VERSION 5.8 ;
BUSBITCHARS "[]" ;
DIVIDERCHAR "/" ;
UNITS
    DATABASE MICRONS 1000 ;
END UNITS

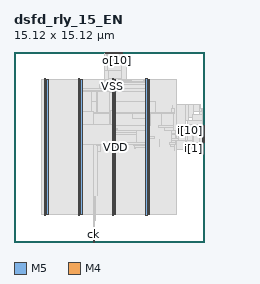
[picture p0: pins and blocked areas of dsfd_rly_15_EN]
MACRO dsfd_rly_15_EN
  FOREIGN dsfd_rly_15_EN 0 0 ;
  CLASS BLOCK ;
  SIZE 15.12 BY 15.12 ;
  PIN ck
    DIRECTION INPUT ;
    USE SIGNAL ;
    PORT
      LAYER M5 ;
        RECT  6.288 0 6.312 0.084 ;
    END
  END ck
  PIN i[0]
    DIRECTION INPUT ;
    USE SIGNAL ;
    PORT
      LAYER M4 ;
        RECT  15.036 7.92 15.12 7.944 ;
    END
  END i[0]
  PIN i[10]
    DIRECTION INPUT ;
    USE SIGNAL ;
    PORT
      LAYER M4 ;
        RECT  15.036 8.88 15.12 8.904 ;
    END
  END i[10]
  PIN i[11]
    DIRECTION INPUT ;
    USE SIGNAL ;
    PORT
      LAYER M4 ;
        RECT  15.036 8.976 15.12 9 ;
    END
  END i[11]
  PIN i[12]
    DIRECTION INPUT ;
    USE SIGNAL ;
    PORT
      LAYER M4 ;
        RECT  15.036 9.072 15.12 9.096 ;
    END
  END i[12]
  PIN i[13]
    DIRECTION INPUT ;
    USE SIGNAL ;
    PORT
      LAYER M4 ;
        RECT  15.036 9.168 15.12 9.192 ;
    END
  END i[13]
  PIN i[14]
    DIRECTION INPUT ;
    USE SIGNAL ;
    PORT
      LAYER M4 ;
        RECT  15.036 9.264 15.12 9.288 ;
    END
  END i[14]
  PIN i[1]
    DIRECTION INPUT ;
    USE SIGNAL ;
    PORT
      LAYER M4 ;
        RECT  15.036 8.016 15.12 8.04 ;
    END
  END i[1]
  PIN i[2]
    DIRECTION INPUT ;
    USE SIGNAL ;
    PORT
      LAYER M4 ;
        RECT  15.036 8.112 15.12 8.136 ;
    END
  END i[2]
  PIN i[3]
    DIRECTION INPUT ;
    USE SIGNAL ;
    PORT
      LAYER M4 ;
        RECT  15.036 8.208 15.12 8.232 ;
    END
  END i[3]
  PIN i[4]
    DIRECTION INPUT ;
    USE SIGNAL ;
    PORT
      LAYER M4 ;
        RECT  15.036 8.304 15.12 8.328 ;
    END
  END i[4]
  PIN i[5]
    DIRECTION INPUT ;
    USE SIGNAL ;
    PORT
      LAYER M4 ;
        RECT  15.036 8.4 15.12 8.424 ;
    END
  END i[5]
  PIN i[6]
    DIRECTION INPUT ;
    USE SIGNAL ;
    PORT
      LAYER M4 ;
        RECT  15.036 8.496 15.12 8.52 ;
    END
  END i[6]
  PIN i[7]
    DIRECTION INPUT ;
    USE SIGNAL ;
    PORT
      LAYER M4 ;
        RECT  15.036 8.592 15.12 8.616 ;
    END
  END i[7]
  PIN i[8]
    DIRECTION INPUT ;
    USE SIGNAL ;
    PORT
      LAYER M4 ;
        RECT  15.036 8.688 15.12 8.712 ;
    END
  END i[8]
  PIN i[9]
    DIRECTION INPUT ;
    USE SIGNAL ;
    PORT
      LAYER M4 ;
        RECT  15.036 8.784 15.12 8.808 ;
    END
  END i[9]
  PIN o[0]
    DIRECTION OUTPUT ;
    USE SIGNAL ;
    PORT
      LAYER M5 ;
        RECT  7.248 15.036 7.272 15.12 ;
    END
  END o[0]
  PIN o[10]
    DIRECTION OUTPUT ;
    USE SIGNAL ;
    PORT
      LAYER M5 ;
        RECT  8.208 15.036 8.232 15.12 ;
    END
  END o[10]
  PIN o[11]
    DIRECTION OUTPUT ;
    USE SIGNAL ;
    PORT
      LAYER M5 ;
        RECT  8.304 15.036 8.328 15.12 ;
    END
  END o[11]
  PIN o[12]
    DIRECTION OUTPUT ;
    USE SIGNAL ;
    PORT
      LAYER M5 ;
        RECT  8.4 15.036 8.424 15.12 ;
    END
  END o[12]
  PIN o[13]
    DIRECTION OUTPUT ;
    USE SIGNAL ;
    PORT
      LAYER M5 ;
        RECT  8.496 15.036 8.52 15.12 ;
    END
  END o[13]
  PIN o[14]
    DIRECTION OUTPUT ;
    USE SIGNAL ;
    PORT
      LAYER M5 ;
        RECT  8.592 15.036 8.616 15.12 ;
    END
  END o[14]
  PIN o[1]
    DIRECTION OUTPUT ;
    USE SIGNAL ;
    PORT
      LAYER M5 ;
        RECT  7.344 15.036 7.368 15.12 ;
    END
  END o[1]
  PIN o[2]
    DIRECTION OUTPUT ;
    USE SIGNAL ;
    PORT
      LAYER M5 ;
        RECT  7.44 15.036 7.464 15.12 ;
    END
  END o[2]
  PIN o[3]
    DIRECTION OUTPUT ;
    USE SIGNAL ;
    PORT
      LAYER M5 ;
        RECT  7.536 15.036 7.56 15.12 ;
    END
  END o[3]
  PIN o[4]
    DIRECTION OUTPUT ;
    USE SIGNAL ;
    PORT
      LAYER M5 ;
        RECT  7.632 15.036 7.656 15.12 ;
    END
  END o[4]
  PIN o[5]
    DIRECTION OUTPUT ;
    USE SIGNAL ;
    PORT
      LAYER M5 ;
        RECT  7.728 15.036 7.752 15.12 ;
    END
  END o[5]
  PIN o[6]
    DIRECTION OUTPUT ;
    USE SIGNAL ;
    PORT
      LAYER M5 ;
        RECT  7.824 15.036 7.848 15.12 ;
    END
  END o[6]
  PIN o[7]
    DIRECTION OUTPUT ;
    USE SIGNAL ;
    PORT
      LAYER M5 ;
        RECT  7.92 15.036 7.944 15.12 ;
    END
  END o[7]
  PIN o[8]
    DIRECTION OUTPUT ;
    USE SIGNAL ;
    PORT
      LAYER M5 ;
        RECT  8.016 15.036 8.04 15.12 ;
    END
  END o[8]
  PIN o[9]
    DIRECTION OUTPUT ;
    USE SIGNAL ;
    PORT
      LAYER M5 ;
        RECT  8.112 15.036 8.136 15.12 ;
    END
  END o[9]
  PIN rs
    DIRECTION INPUT ;
    USE SIGNAL ;
    PORT
      LAYER M5 ;
        RECT  6.384 0 6.408 0.084 ;
    END
  END rs
  PIN VDD
    DIRECTION INOUT ;
    USE POWER ;
    PORT
      LAYER M5 ;
        RECT  10.692 2.151 10.812 12.969 ;
        RECT  7.992 2.151 8.112 12.969 ;
        RECT  5.292 2.151 5.412 12.969 ;
        RECT  2.592 2.151 2.712 12.969 ;
    END
  END VDD
  PIN VSS
    DIRECTION INOUT ;
    USE GROUND ;
    PORT
      LAYER M5 ;
        RECT  10.5 2.137 10.62 12.983 ;
        RECT  7.8 2.137 7.92 12.983 ;
        RECT  5.1 2.137 5.22 12.983 ;
        RECT  2.4 2.137 2.52 12.983 ;
    END
  END VSS
  OBS
    LAYER RVTN ;
     RECT  2.16 2.16 12.96 2.295 ;
     RECT  2.16 2.565 12.96 2.835 ;
     RECT  2.16 3.105 12.96 3.375 ;
     RECT  2.16 3.645 12.96 3.915 ;
     RECT  2.16 4.185 12.96 4.455 ;
     RECT  2.16 4.725 12.96 4.995 ;
     RECT  2.16 5.265 12.96 5.535 ;
     RECT  2.16 5.805 12.96 6.075 ;
     RECT  2.16 6.345 12.96 6.615 ;
     RECT  2.16 6.885 12.96 7.155 ;
     RECT  2.16 7.425 12.96 7.695 ;
     RECT  2.16 7.965 12.96 8.235 ;
     RECT  2.16 8.505 12.96 8.775 ;
     RECT  2.16 9.045 12.96 9.315 ;
     RECT  2.16 9.585 12.96 9.855 ;
     RECT  2.16 10.125 12.96 10.395 ;
     RECT  2.16 10.665 12.96 10.935 ;
     RECT  2.16 11.205 12.96 11.475 ;
     RECT  2.16 11.745 12.96 12.015 ;
     RECT  2.16 12.285 12.96 12.555 ;
     RECT  2.16 12.825 12.96 12.96 ;
    LAYER RVTP ;
     RECT  2.16 2.295 12.96 2.565 ;
     RECT  2.16 2.835 12.96 3.105 ;
     RECT  2.16 3.375 12.96 3.645 ;
     RECT  2.16 3.915 12.96 4.185 ;
     RECT  2.16 4.455 12.96 4.725 ;
     RECT  2.16 4.995 12.96 5.265 ;
     RECT  2.16 5.535 12.96 5.805 ;
     RECT  2.16 6.075 12.96 6.345 ;
     RECT  2.16 6.615 12.96 6.885 ;
     RECT  2.16 7.155 12.96 7.425 ;
     RECT  2.16 7.695 12.96 7.965 ;
     RECT  2.16 8.235 12.96 8.505 ;
     RECT  2.16 8.775 12.96 9.045 ;
     RECT  2.16 9.315 12.96 9.585 ;
     RECT  2.16 9.855 12.96 10.125 ;
     RECT  2.16 10.395 12.96 10.665 ;
     RECT  2.16 10.935 12.96 11.205 ;
     RECT  2.16 11.475 12.96 11.745 ;
     RECT  2.16 12.015 12.96 12.285 ;
     RECT  2.16 12.555 12.96 12.825 ;
    LAYER M1 ;
     RECT  2.16 2.151 12.96 12.969 ;
    LAYER M2 ;
     RECT  2.16 2.151 12.96 12.969 ;
     RECT  12.96 7.398 13.667 10.926 ;
     RECT  13.667 9.63 13.847 10.926 ;
     RECT  13.667 7.398 14.243 8.802 ;
     RECT  14.243 7.398 14.279 7.956 ;
     RECT  13.847 9.9 14.279 10.926 ;
     RECT  14.279 7.938 14.315 7.956 ;
     RECT  14.279 10.368 14.819 10.926 ;
     RECT  14.819 10.368 14.963 10.656 ;
     RECT  14.963 10.368 15.035 10.386 ;
    LAYER M3 ;
     RECT  2.415 2.143 2.505 2.413 ;
     RECT  5.115 2.143 5.205 2.413 ;
     RECT  7.815 2.143 7.905 2.413 ;
     RECT  10.515 2.143 10.605 2.413 ;
     RECT  6.444 1.723 6.462 3.605 ;
     RECT  6.66 3.721 6.678 7.231 ;
     RECT  7.815 2.413 8.097 7.465 ;
     RECT  9.648 7.429 9.666 7.465 ;
     RECT  7.815 7.465 8.478 7.501 ;
     RECT  9.612 7.465 9.666 7.501 ;
     RECT  10.515 2.413 10.797 7.501 ;
     RECT  12.744 7.321 12.762 7.627 ;
     RECT  6.66 7.231 6.894 7.699 ;
     RECT  7.815 7.501 8.55 7.699 ;
     RECT  9.612 7.501 10.797 7.699 ;
     RECT  12.456 7.627 12.762 7.735 ;
     RECT  7.812 7.699 8.55 7.765 ;
     RECT  6.552 7.699 6.894 7.771 ;
     RECT  7.668 7.765 8.55 7.771 ;
     RECT  9.504 7.699 10.797 7.771 ;
     RECT  12.456 7.735 12.834 7.771 ;
     RECT  14.256 7.393 14.274 7.771 ;
     RECT  6.408 7.771 10.797 7.889 ;
     RECT  12.348 7.771 12.834 7.925 ;
     RECT  13.716 7.771 14.274 7.933 ;
     RECT  12.528 7.925 12.834 8.107 ;
     RECT  13.716 7.933 14.31 8.107 ;
     RECT  11.556 7.591 11.574 8.159 ;
     RECT  10.515 7.889 10.797 8.203 ;
     RECT  12.528 8.107 14.31 8.267 ;
     RECT  13.644 8.267 14.31 8.395 ;
     RECT  10.515 8.203 11.142 8.429 ;
     RECT  6.408 7.889 9.738 8.581 ;
     RECT  5.115 2.413 5.397 8.683 ;
     RECT  6.228 8.581 9.738 8.683 ;
     RECT  5.115 8.683 9.738 8.843 ;
     RECT  6.192 8.843 9.738 8.851 ;
     RECT  10.515 8.429 10.797 8.851 ;
     RECT  12.528 8.267 12.834 8.851 ;
     RECT  11.988 8.851 12.834 8.879 ;
     RECT  11.988 8.879 12.69 9.085 ;
     RECT  11.52 9.085 12.69 9.275 ;
     RECT  6.192 8.851 10.797 9.283 ;
     RECT  13.644 8.395 15.03 9.383 ;
     RECT  13.824 9.383 15.03 9.653 ;
     RECT  14.22 9.653 15.03 10.121 ;
     RECT  6.192 9.283 10.854 10.201 ;
     RECT  11.736 9.275 12.69 10.201 ;
     RECT  6.192 10.201 12.762 10.319 ;
     RECT  14.796 10.121 15.03 10.391 ;
     RECT  12.564 10.319 12.762 10.589 ;
     RECT  12.6 10.589 12.762 10.625 ;
     RECT  14.796 10.391 14.958 10.661 ;
     RECT  12.6 10.625 12.618 10.859 ;
     RECT  14.796 10.661 14.814 10.931 ;
     RECT  6.192 10.319 11.286 11.201 ;
     RECT  5.115 8.843 5.397 11.995 ;
     RECT  6.192 11.201 10.797 11.995 ;
     RECT  5.115 11.995 10.797 12.209 ;
     RECT  6.804 12.209 10.797 12.245 ;
     RECT  6.84 12.245 10.797 12.551 ;
     RECT  2.415 2.413 2.697 12.707 ;
     RECT  5.115 12.209 5.397 12.707 ;
     RECT  6.984 12.551 10.797 12.707 ;
     RECT  6.984 12.707 10.605 12.749 ;
     RECT  6.984 12.749 9.342 12.785 ;
     RECT  7.2 12.785 9.342 12.821 ;
     RECT  10.332 12.749 10.605 12.821 ;
     RECT  7.2 12.821 9.054 12.929 ;
     RECT  2.415 12.707 2.505 12.977 ;
     RECT  5.115 12.707 5.205 12.977 ;
     RECT  10.515 12.821 10.605 12.977 ;
     RECT  7.2 12.929 8.982 14.237 ;
     RECT  7.2 14.237 8.478 14.717 ;
     RECT  7.2 14.717 7.398 15.005 ;
     RECT  8.208 14.717 8.478 15.005 ;
    LAYER M4 ;
     RECT  2.408 2.148 2.512 12.972 ;
     RECT  2.512 2.418 2.704 12.702 ;
     RECT  5.108 2.148 5.212 12.972 ;
     RECT  5.212 2.418 5.404 12.702 ;
     RECT  5.404 8.688 6.397 8.712 ;
     RECT  6.373 1.728 6.473 1.752 ;
     RECT  5.404 10.32 6.565 10.344 ;
     RECT  5.404 12 6.565 12.024 ;
     RECT  6.565 10.32 6.611 12.024 ;
     RECT  6.397 7.776 6.853 8.712 ;
     RECT  7.297 13.632 7.475 13.656 ;
     RECT  6.853 7.776 7.585 9.336 ;
     RECT  6.611 10.32 7.585 11.976 ;
     RECT  7.189 14.976 7.765 15 ;
     RECT  7.585 7.776 7.808 11.976 ;
     RECT  7.685 13.056 7.808 13.128 ;
     RECT  7.808 2.148 7.912 13.128 ;
     RECT  7.912 2.418 7.985 13.128 ;
     RECT  7.985 2.418 8.104 13.08 ;
     RECT  8.104 11.184 8.165 11.208 ;
     RECT  8.104 8.976 8.237 9 ;
     RECT  8.104 12.288 8.317 13.08 ;
     RECT  8.317 13.008 8.453 13.08 ;
     RECT  7.765 14.688 8.489 15 ;
     RECT  8.453 13.008 8.561 13.032 ;
     RECT  8.104 7.92 8.597 7.944 ;
     RECT  8.581 14.208 8.993 14.232 ;
     RECT  9.133 10.224 9.421 10.248 ;
     RECT  9.421 9.792 10.508 10.248 ;
     RECT  10.508 2.148 10.612 12.972 ;
     RECT  10.612 2.418 10.804 12.702 ;
     RECT  12.589 8.592 13.057 8.616 ;
     RECT  13.057 8.112 13.633 8.616 ;
     RECT  13.633 8.112 13.813 9 ;
     RECT  13.813 8.112 14.209 9.096 ;
     RECT  14.209 8.016 14.245 9.192 ;
     RECT  14.245 7.92 14.785 9.192 ;
     RECT  14.785 7.92 15.084 9.288 ;
    LAYER M5 ;
     RECT  6.288 0.016 6.408 1.763 ;
     RECT  2.4 2.137 2.52 2.151 ;
     RECT  5.1 2.137 5.22 2.151 ;
     RECT  6.288 1.763 6.312 2.151 ;
     RECT  7.8 2.137 7.92 2.151 ;
     RECT  10.5 2.137 10.62 2.151 ;
     RECT  5.1 2.151 6.312 7.765 ;
     RECT  7.8 2.151 8.112 7.765 ;
     RECT  5.1 7.765 8.112 9.347 ;
     RECT  5.1 9.347 6.312 10.355 ;
     RECT  7.68 9.347 8.112 10.451 ;
     RECT  7.8 10.451 8.112 11.893 ;
     RECT  6.576 11.173 6.6 11.941 ;
     RECT  7.632 11.893 8.112 11.941 ;
     RECT  6.576 11.941 8.112 12.035 ;
     RECT  7.536 12.035 8.112 12.277 ;
     RECT  2.4 2.151 2.712 12.969 ;
     RECT  5.1 10.355 5.412 12.969 ;
     RECT  10.5 2.151 10.812 12.969 ;
     RECT  2.4 12.969 2.52 12.983 ;
     RECT  5.1 12.969 5.22 12.983 ;
     RECT  10.5 12.969 10.62 12.983 ;
     RECT  7.536 12.277 8.28 12.997 ;
     RECT  7.536 12.997 8.52 13.621 ;
     RECT  7.44 13.621 8.52 14.197 ;
     RECT  7.44 14.197 8.616 14.965 ;
     RECT  7.248 14.965 8.616 15.056 ;
  END
END dsfd_rly_15_EN
END LIBRARY
